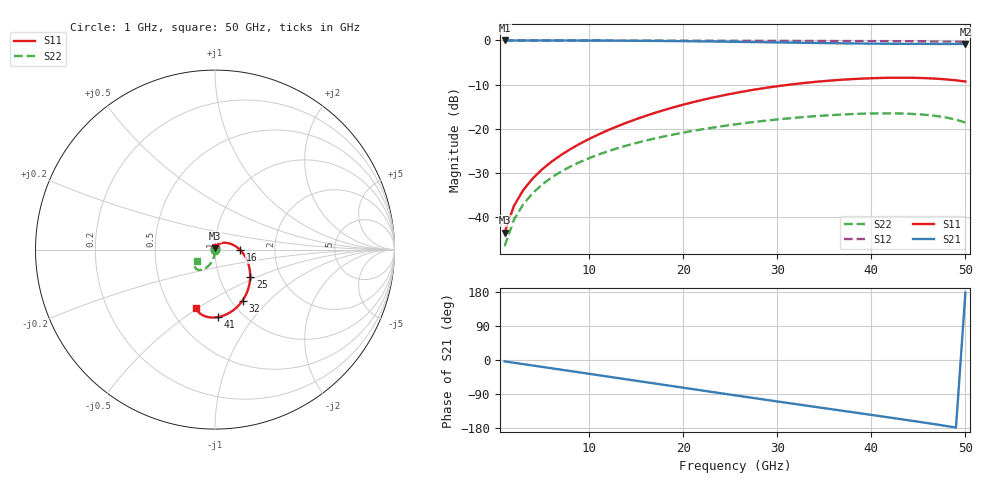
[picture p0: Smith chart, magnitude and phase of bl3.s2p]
! Impedora 0.10.0 via model, case bl3 (fullwave/cases.json), 2026-11-19
! Blind via as bl2 with a pad barely larger than the drill: 0.26 mm pad on the 0.2 mm drill, under the 0.6 mm antipad: with its pads and traces, ports at the far end of each trace, after the 3D port calibration.
! Ports: 1 = upper end, 2 = lower end, 50 ohm.
! Compared with the edge 3D mesh.
# Hz S RI R 50
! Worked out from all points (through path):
!   50 points, 1 GHz to 50 GHz, reference 50 ohm
!   highest |S21| = 0.00 dB at 1 GHz (marker M1); lowest = -0.8 dB at 50 GHz (marker M2)
!   group delay of S21, straight-line fit = 10.1 ps
!   lowest |S11| = -43.5 dB at 1 GHz (marker M3), VSWR 1.01, Z = 50.1 + j0.667 ohm
!   |S11| at or under -10 dB: start of sweep to 31.32 GHz
!   |S22| runs from -46.6 to -16.5 dB; largest |S21 - S12| = 1.8
!   S11 on the Smith chart (normalised r, x): 1 GHz: 1.00, +0.01; 16 GHz: 1.33, -0.01; 25 GHz: 1.40, -0.45; 32 GHz: 1.12, -0.71; 41 GHz: 0.77, -0.68; 50 GHz: 0.66, -0.49
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1e9  0.000763 0.00667  0.998 -0.0635  0.9999 -0.0131  -8.04e-05 -0.0047
2e9  0.00304 0.0131  0.9918 -0.1267  0.9996 -0.0262  -0.000322 -0.0094
3e9  0.0068 0.0192  0.9816 -0.1894  0.9991 -0.0393  -0.000725 -0.0141
4e9  0.012 0.0248  0.9674 -0.2514  0.9984 -0.0524  -0.00129 -0.0187
5e9  0.0185 0.0296  0.9493 -0.3123  0.9975 -0.0655  -0.00201 -0.0234
7e9  0.0352 0.0363  0.9012 -0.43  0.9952 -0.0917  -0.00395 -0.0326
1e10  0.0674 0.0372  0.8015 -0.5925  0.9902 -0.1308  -0.00804 -0.046
1.3e10  0.104 0.0246  0.6718 -0.7323  0.9835 -0.1698  -0.0135 -0.0587
1.6e10  0.1401 -0.00239  0.5174 -0.8434  0.9751 -0.2085  -0.0203 -0.0707
1.8e10  0.1612 -0.0281  0.4039 -0.8991  0.9685 -0.2343  -0.0255 -0.0782
2.1e10  0.1848 -0.0762  0.2236 -0.9527  0.9571 -0.2727  -0.0342 -0.0883
2.5e10  0.1962 -0.152  -0.0229 -0.9667  0.9391 -0.3237  -0.0473 -0.0997
2.6e10  0.195 -0.1719  -0.0837 -0.9601  0.9341 -0.3364  -0.0509 -0.1021
2.9e10  0.1812 -0.2304  -0.2596 -0.9177  0.9178 -0.3744  -0.0618 -0.1081
3.2e10  0.1534 -0.2838  -0.4213 -0.8441  0.8994 -0.4125  -0.073 -0.112
3.4e10  0.1282 -0.3144  -0.5189 -0.78  0.8858 -0.4379  -0.0805 -0.1133
3.8e10  0.0669 -0.3593  -0.6854 -0.6216  0.8552 -0.489  -0.0948 -0.1123
4.1e10  0.0159 -0.3762  -0.783 -0.4809  0.8285 -0.528  -0.104 -0.1076
4.2e10  -0.00116 -0.3782  -0.81 -0.4304  0.8187 -0.5413  -0.1066 -0.1051
4.5e10  -0.0497 -0.3734  -0.8736 -0.2687  0.7856 -0.5822  -0.1116 -0.0944
4.7e10  -0.0774 -0.3606  -0.9002 -0.1525  0.7591 -0.6106  -0.1112 -0.084
5e10  -0.1052 -0.3266  -0.9108 0.0357  0.7081 -0.655  -0.0998 -0.0628
